VERSION 5.7 ;
  NOWIREEXTENSIONATPIN ON ;
  DIVIDERCHAR "/" ;
  BUSBITCHARS "[]" ;
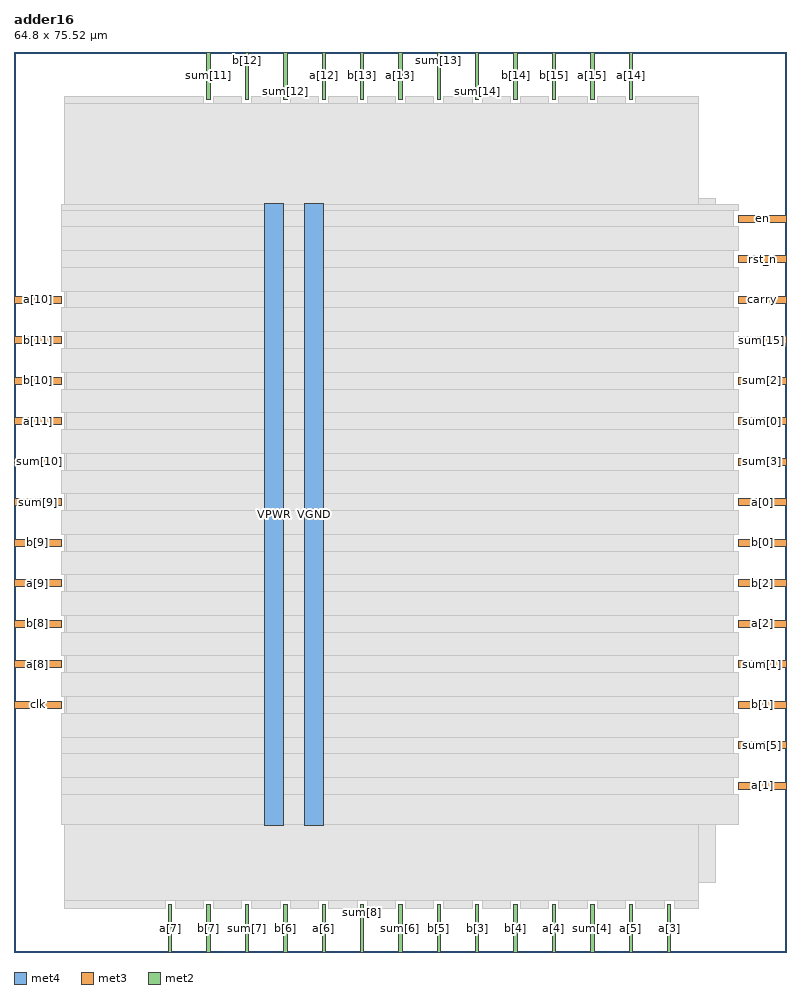
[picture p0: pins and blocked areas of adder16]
MACRO adder16
  CLASS BLOCK ;
  FOREIGN adder16 ;
  ORIGIN 0.000 0.000 ;
  SIZE 64.800 BY 75.520 ;
  PIN VGND
    DIRECTION INOUT ;
    USE GROUND ;
    PORT
      LAYER met4 ;
        RECT 24.340 10.640 25.940 62.800 ;
    END
  END VGND
  PIN VPWR
    DIRECTION INOUT ;
    USE POWER ;
    PORT
      LAYER met4 ;
        RECT 21.040 10.640 22.640 62.800 ;
    END
  END VPWR
  PIN a[0]
    DIRECTION INPUT ;
    USE SIGNAL ;
    ANTENNAGATEAREA 0.196500 ;
    PORT
      LAYER met3 ;
        RECT 60.800 37.440 64.800 38.040 ;
    END
  END a[0]
  PIN a[10]
    DIRECTION INPUT ;
    USE SIGNAL ;
    ANTENNAGATEAREA 0.196500 ;
    PORT
      LAYER met3 ;
        RECT 0.000 54.440 4.000 55.040 ;
    END
  END a[10]
  PIN a[11]
    DIRECTION INPUT ;
    USE SIGNAL ;
    ANTENNAGATEAREA 0.196500 ;
    PORT
      LAYER met3 ;
        RECT 0.000 44.240 4.000 44.840 ;
    END
  END a[11]
  PIN a[12]
    DIRECTION INPUT ;
    USE SIGNAL ;
    ANTENNAGATEAREA 0.196500 ;
    PORT
      LAYER met2 ;
        RECT 25.850 71.520 26.130 75.520 ;
    END
  END a[12]
  PIN a[13]
    DIRECTION INPUT ;
    USE SIGNAL ;
    ANTENNAGATEAREA 0.196500 ;
    PORT
      LAYER met2 ;
        RECT 32.290 71.520 32.570 75.520 ;
    END
  END a[13]
  PIN a[14]
    DIRECTION INPUT ;
    USE SIGNAL ;
    ANTENNAGATEAREA 0.196500 ;
    PORT
      LAYER met2 ;
        RECT 51.610 71.520 51.890 75.520 ;
    END
  END a[14]
  PIN a[15]
    DIRECTION INPUT ;
    USE SIGNAL ;
    ANTENNAGATEAREA 0.196500 ;
    PORT
      LAYER met2 ;
        RECT 48.390 71.520 48.670 75.520 ;
    END
  END a[15]
  PIN a[1]
    DIRECTION INPUT ;
    USE SIGNAL ;
    ANTENNAGATEAREA 0.196500 ;
    PORT
      LAYER met3 ;
        RECT 60.800 13.640 64.800 14.240 ;
    END
  END a[1]
  PIN a[2]
    DIRECTION INPUT ;
    USE SIGNAL ;
    ANTENNAGATEAREA 0.196500 ;
    PORT
      LAYER met3 ;
        RECT 60.800 27.240 64.800 27.840 ;
    END
  END a[2]
  PIN a[3]
    DIRECTION INPUT ;
    USE SIGNAL ;
    ANTENNAGATEAREA 0.196500 ;
    PORT
      LAYER met2 ;
        RECT 54.830 0.000 55.110 4.000 ;
    END
  END a[3]
  PIN a[4]
    DIRECTION INPUT ;
    USE SIGNAL ;
    ANTENNAGATEAREA 0.196500 ;
    PORT
      LAYER met2 ;
        RECT 45.170 0.000 45.450 4.000 ;
    END
  END a[4]
  PIN a[5]
    DIRECTION INPUT ;
    USE SIGNAL ;
    ANTENNAGATEAREA 0.196500 ;
    PORT
      LAYER met2 ;
        RECT 51.610 0.000 51.890 4.000 ;
    END
  END a[5]
  PIN a[6]
    DIRECTION INPUT ;
    USE SIGNAL ;
    ANTENNAGATEAREA 0.495000 ;
    PORT
      LAYER met2 ;
        RECT 25.850 0.000 26.130 4.000 ;
    END
  END a[6]
  PIN a[7]
    DIRECTION INPUT ;
    USE SIGNAL ;
    ANTENNAGATEAREA 0.495000 ;
    PORT
      LAYER met2 ;
        RECT 12.970 0.000 13.250 4.000 ;
    END
  END a[7]
  PIN a[8]
    DIRECTION INPUT ;
    USE SIGNAL ;
    ANTENNAGATEAREA 0.196500 ;
    PORT
      LAYER met3 ;
        RECT 0.000 23.840 4.000 24.440 ;
    END
  END a[8]
  PIN a[9]
    DIRECTION INPUT ;
    USE SIGNAL ;
    ANTENNAGATEAREA 0.196500 ;
    PORT
      LAYER met3 ;
        RECT 0.000 30.640 4.000 31.240 ;
    END
  END a[9]
  PIN b[0]
    DIRECTION INPUT ;
    USE SIGNAL ;
    ANTENNAGATEAREA 0.196500 ;
    PORT
      LAYER met3 ;
        RECT 60.800 34.040 64.800 34.640 ;
    END
  END b[0]
  PIN b[10]
    DIRECTION INPUT ;
    USE SIGNAL ;
    ANTENNAGATEAREA 0.196500 ;
    PORT
      LAYER met3 ;
        RECT 0.000 47.640 4.000 48.240 ;
    END
  END b[10]
  PIN b[11]
    DIRECTION INPUT ;
    USE SIGNAL ;
    ANTENNAGATEAREA 0.196500 ;
    PORT
      LAYER met3 ;
        RECT 0.000 51.040 4.000 51.640 ;
    END
  END b[11]
  PIN b[12]
    DIRECTION INPUT ;
    USE SIGNAL ;
    ANTENNAGATEAREA 0.196500 ;
    PORT
      LAYER met2 ;
        RECT 19.410 71.520 19.690 75.520 ;
    END
  END b[12]
  PIN b[13]
    DIRECTION INPUT ;
    USE SIGNAL ;
    ANTENNAGATEAREA 0.196500 ;
    PORT
      LAYER met2 ;
        RECT 29.070 71.520 29.350 75.520 ;
    END
  END b[13]
  PIN b[14]
    DIRECTION INPUT ;
    USE SIGNAL ;
    ANTENNAGATEAREA 0.196500 ;
    PORT
      LAYER met2 ;
        RECT 41.950 71.520 42.230 75.520 ;
    END
  END b[14]
  PIN b[15]
    DIRECTION INPUT ;
    USE SIGNAL ;
    ANTENNAGATEAREA 0.196500 ;
    PORT
      LAYER met2 ;
        RECT 45.170 71.520 45.450 75.520 ;
    END
  END b[15]
  PIN b[1]
    DIRECTION INPUT ;
    USE SIGNAL ;
    ANTENNAGATEAREA 0.196500 ;
    PORT
      LAYER met3 ;
        RECT 60.800 20.440 64.800 21.040 ;
    END
  END b[1]
  PIN b[2]
    DIRECTION INPUT ;
    USE SIGNAL ;
    ANTENNAGATEAREA 0.196500 ;
    PORT
      LAYER met3 ;
        RECT 60.800 30.640 64.800 31.240 ;
    END
  END b[2]
  PIN b[3]
    DIRECTION INPUT ;
    USE SIGNAL ;
    ANTENNAGATEAREA 0.196500 ;
    PORT
      LAYER met2 ;
        RECT 38.730 0.000 39.010 4.000 ;
    END
  END b[3]
  PIN b[4]
    DIRECTION INPUT ;
    USE SIGNAL ;
    ANTENNAGATEAREA 0.196500 ;
    PORT
      LAYER met2 ;
        RECT 41.950 0.000 42.230 4.000 ;
    END
  END b[4]
  PIN b[5]
    DIRECTION INPUT ;
    USE SIGNAL ;
    ANTENNAGATEAREA 0.196500 ;
    PORT
      LAYER met2 ;
        RECT 35.510 0.000 35.790 4.000 ;
    END
  END b[5]
  PIN b[6]
    DIRECTION INPUT ;
    USE SIGNAL ;
    ANTENNAGATEAREA 0.495000 ;
    PORT
      LAYER met2 ;
        RECT 22.630 0.000 22.910 4.000 ;
    END
  END b[6]
  PIN b[7]
    DIRECTION INPUT ;
    USE SIGNAL ;
    ANTENNAGATEAREA 0.495000 ;
    PORT
      LAYER met2 ;
        RECT 16.190 0.000 16.470 4.000 ;
    END
  END b[7]
  PIN b[8]
    DIRECTION INPUT ;
    USE SIGNAL ;
    ANTENNAGATEAREA 0.196500 ;
    PORT
      LAYER met3 ;
        RECT 0.000 27.240 4.000 27.840 ;
    END
  END b[8]
  PIN b[9]
    DIRECTION INPUT ;
    USE SIGNAL ;
    ANTENNAGATEAREA 0.196500 ;
    PORT
      LAYER met3 ;
        RECT 0.000 34.040 4.000 34.640 ;
    END
  END b[9]
  PIN carry
    DIRECTION OUTPUT ;
    USE SIGNAL ;
    ANTENNADIFFAREA 0.445500 ;
    PORT
      LAYER met3 ;
        RECT 60.800 54.440 64.800 55.040 ;
    END
  END carry
  PIN clk
    DIRECTION INPUT ;
    USE SIGNAL ;
    ANTENNAGATEAREA 0.852000 ;
    PORT
      LAYER met3 ;
        RECT 0.000 20.440 4.000 21.040 ;
    END
  END clk
  PIN en
    DIRECTION INPUT ;
    USE SIGNAL ;
    ANTENNAGATEAREA 0.196500 ;
    PORT
      LAYER met3 ;
        RECT 60.800 61.240 64.800 61.840 ;
    END
  END en
  PIN rst_n
    DIRECTION INPUT ;
    USE SIGNAL ;
    ANTENNAGATEAREA 0.126000 ;
    PORT
      LAYER met3 ;
        RECT 60.800 57.840 64.800 58.440 ;
    END
  END rst_n
  PIN sum[0]
    DIRECTION OUTPUT ;
    USE SIGNAL ;
    ANTENNADIFFAREA 0.445500 ;
    PORT
      LAYER met3 ;
        RECT 60.800 44.240 64.800 44.840 ;
    END
  END sum[0]
  PIN sum[10]
    DIRECTION OUTPUT ;
    USE SIGNAL ;
    ANTENNADIFFAREA 0.445500 ;
    PORT
      LAYER met3 ;
        RECT 0.000 40.840 4.000 41.440 ;
    END
  END sum[10]
  PIN sum[11]
    DIRECTION OUTPUT ;
    USE SIGNAL ;
    ANTENNADIFFAREA 0.445500 ;
    PORT
      LAYER met2 ;
        RECT 16.190 71.520 16.470 75.520 ;
    END
  END sum[11]
  PIN sum[12]
    DIRECTION OUTPUT ;
    USE SIGNAL ;
    ANTENNADIFFAREA 0.445500 ;
    PORT
      LAYER met2 ;
        RECT 22.630 71.520 22.910 75.520 ;
    END
  END sum[12]
  PIN sum[13]
    DIRECTION OUTPUT ;
    USE SIGNAL ;
    ANTENNADIFFAREA 0.445500 ;
    PORT
      LAYER met2 ;
        RECT 35.510 71.520 35.790 75.520 ;
    END
  END sum[13]
  PIN sum[14]
    DIRECTION OUTPUT ;
    USE SIGNAL ;
    ANTENNADIFFAREA 0.445500 ;
    PORT
      LAYER met2 ;
        RECT 38.730 71.520 39.010 75.520 ;
    END
  END sum[14]
  PIN sum[15]
    DIRECTION OUTPUT ;
    USE SIGNAL ;
    ANTENNADIFFAREA 0.445500 ;
    PORT
      LAYER met3 ;
        RECT 60.800 51.040 64.800 51.640 ;
    END
  END sum[15]
  PIN sum[1]
    DIRECTION OUTPUT ;
    USE SIGNAL ;
    ANTENNADIFFAREA 0.445500 ;
    PORT
      LAYER met3 ;
        RECT 60.800 23.840 64.800 24.440 ;
    END
  END sum[1]
  PIN sum[2]
    DIRECTION OUTPUT ;
    USE SIGNAL ;
    ANTENNADIFFAREA 0.445500 ;
    PORT
      LAYER met3 ;
        RECT 60.800 47.640 64.800 48.240 ;
    END
  END sum[2]
  PIN sum[3]
    DIRECTION OUTPUT ;
    USE SIGNAL ;
    ANTENNADIFFAREA 0.445500 ;
    PORT
      LAYER met3 ;
        RECT 60.800 40.840 64.800 41.440 ;
    END
  END sum[3]
  PIN sum[4]
    DIRECTION OUTPUT ;
    USE SIGNAL ;
    ANTENNADIFFAREA 0.445500 ;
    PORT
      LAYER met2 ;
        RECT 48.390 0.000 48.670 4.000 ;
    END
  END sum[4]
  PIN sum[5]
    DIRECTION OUTPUT ;
    USE SIGNAL ;
    ANTENNADIFFAREA 0.445500 ;
    PORT
      LAYER met3 ;
        RECT 60.800 17.040 64.800 17.640 ;
    END
  END sum[5]
  PIN sum[6]
    DIRECTION OUTPUT ;
    USE SIGNAL ;
    ANTENNADIFFAREA 0.445500 ;
    PORT
      LAYER met2 ;
        RECT 32.290 0.000 32.570 4.000 ;
    END
  END sum[6]
  PIN sum[7]
    DIRECTION OUTPUT ;
    USE SIGNAL ;
    ANTENNADIFFAREA 0.445500 ;
    PORT
      LAYER met2 ;
        RECT 19.410 0.000 19.690 4.000 ;
    END
  END sum[7]
  PIN sum[8]
    DIRECTION OUTPUT ;
    USE SIGNAL ;
    ANTENNADIFFAREA 0.445500 ;
    PORT
      LAYER met2 ;
        RECT 29.070 0.000 29.350 4.000 ;
    END
  END sum[8]
  PIN sum[9]
    DIRECTION OUTPUT ;
    USE SIGNAL ;
    ANTENNADIFFAREA 0.445500 ;
    PORT
      LAYER met3 ;
        RECT 0.000 37.440 4.000 38.040 ;
    END
  END sum[9]
  OBS
      LAYER nwell ;
        RECT 5.330 10.795 59.070 62.750 ;
      LAYER li1 ;
        RECT 5.520 10.795 58.880 62.645 ;
      LAYER met1 ;
        RECT 4.210 5.820 58.880 63.200 ;
      LAYER met2 ;
        RECT 4.230 71.240 15.910 71.810 ;
        RECT 16.750 71.240 19.130 71.810 ;
        RECT 19.970 71.240 22.350 71.810 ;
        RECT 23.190 71.240 25.570 71.810 ;
        RECT 26.410 71.240 28.790 71.810 ;
        RECT 29.630 71.240 32.010 71.810 ;
        RECT 32.850 71.240 35.230 71.810 ;
        RECT 36.070 71.240 38.450 71.810 ;
        RECT 39.290 71.240 41.670 71.810 ;
        RECT 42.510 71.240 44.890 71.810 ;
        RECT 45.730 71.240 48.110 71.810 ;
        RECT 48.950 71.240 51.330 71.810 ;
        RECT 52.170 71.240 57.410 71.810 ;
        RECT 4.230 4.280 57.410 71.240 ;
        RECT 4.230 3.670 12.690 4.280 ;
        RECT 13.530 3.670 15.910 4.280 ;
        RECT 16.750 3.670 19.130 4.280 ;
        RECT 19.970 3.670 22.350 4.280 ;
        RECT 23.190 3.670 25.570 4.280 ;
        RECT 26.410 3.670 28.790 4.280 ;
        RECT 29.630 3.670 32.010 4.280 ;
        RECT 32.850 3.670 35.230 4.280 ;
        RECT 36.070 3.670 38.450 4.280 ;
        RECT 39.290 3.670 41.670 4.280 ;
        RECT 42.510 3.670 44.890 4.280 ;
        RECT 45.730 3.670 48.110 4.280 ;
        RECT 48.950 3.670 51.330 4.280 ;
        RECT 52.170 3.670 54.550 4.280 ;
        RECT 55.390 3.670 57.410 4.280 ;
      LAYER met3 ;
        RECT 3.990 62.240 60.800 62.725 ;
        RECT 3.990 60.840 60.400 62.240 ;
        RECT 3.990 58.840 60.800 60.840 ;
        RECT 3.990 57.440 60.400 58.840 ;
        RECT 3.990 55.440 60.800 57.440 ;
        RECT 4.400 54.040 60.400 55.440 ;
        RECT 3.990 52.040 60.800 54.040 ;
        RECT 4.400 50.640 60.400 52.040 ;
        RECT 3.990 48.640 60.800 50.640 ;
        RECT 4.400 47.240 60.400 48.640 ;
        RECT 3.990 45.240 60.800 47.240 ;
        RECT 4.400 43.840 60.400 45.240 ;
        RECT 3.990 41.840 60.800 43.840 ;
        RECT 4.400 40.440 60.400 41.840 ;
        RECT 3.990 38.440 60.800 40.440 ;
        RECT 4.400 37.040 60.400 38.440 ;
        RECT 3.990 35.040 60.800 37.040 ;
        RECT 4.400 33.640 60.400 35.040 ;
        RECT 3.990 31.640 60.800 33.640 ;
        RECT 4.400 30.240 60.400 31.640 ;
        RECT 3.990 28.240 60.800 30.240 ;
        RECT 4.400 26.840 60.400 28.240 ;
        RECT 3.990 24.840 60.800 26.840 ;
        RECT 4.400 23.440 60.400 24.840 ;
        RECT 3.990 21.440 60.800 23.440 ;
        RECT 4.400 20.040 60.400 21.440 ;
        RECT 3.990 18.040 60.800 20.040 ;
        RECT 3.990 16.640 60.400 18.040 ;
        RECT 3.990 14.640 60.800 16.640 ;
        RECT 3.990 13.240 60.400 14.640 ;
        RECT 3.990 10.715 60.800 13.240 ;
  END
END adder16
END LIBRARY

